VERSION 5.8 ;
BUSBITCHARS "[]" ;
DIVIDERCHAR "/" ;
UNITS
    DATABASE MICRONS 1000 ;
END UNITS

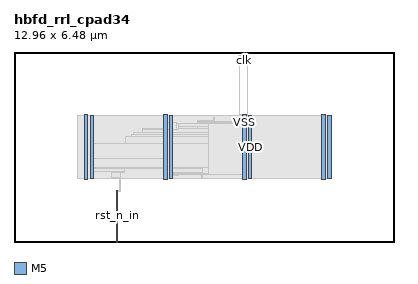
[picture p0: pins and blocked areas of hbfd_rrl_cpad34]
MACRO hbfd_rrl_cpad34
  FOREIGN hbfd_rrl_cpad34 0 0 ;
  CLASS BLOCK ;
  SIZE 12.96 BY 6.48 ;
  PIN clk
    DIRECTION INPUT ;
    USE SIGNAL ;
    PORT
      LAYER M5 ;
        RECT  7.824 6.396 7.848 6.48 ;
    END
  END clk
  PIN rst_n
    DIRECTION OUTPUT ;
    USE SIGNAL ;
    PORT
      LAYER M5 ;
        RECT  7.92 6.396 7.944 6.48 ;
    END
  END rst_n
  PIN rst_n_in
    DIRECTION INPUT ;
    USE SIGNAL ;
    PORT
      LAYER M5 ;
        RECT  3.504 0 3.528 0.084 ;
    END
    PORT
      LAYER M5 ;
        RECT  3.504 0.016 3.528 1.763 ;
    END
  END rst_n_in
  PIN VDD
    DIRECTION INOUT ;
    USE POWER ;
    PORT
      LAYER M5 ;
        RECT  10.692 2.151 10.812 4.329 ;
        RECT  7.992 2.151 8.112 4.329 ;
        RECT  5.292 2.151 5.412 4.329 ;
        RECT  2.592 2.151 2.712 4.329 ;
    END
  END VDD
  PIN VSS
    DIRECTION INOUT ;
    USE GROUND ;
    PORT
      LAYER M5 ;
        RECT  10.5 2.137 10.62 4.343 ;
        RECT  7.8 2.137 7.92 4.343 ;
        RECT  5.1 2.137 5.22 4.343 ;
        RECT  2.4 2.137 2.52 4.343 ;
    END
  END VSS
  # OT_OBS_CLOSED layer=M5 d_um=1.536 added=0
  OBS
    LAYER RVTN ;
     RECT  2.16 2.16 10.8 2.295 ;
     RECT  2.16 2.565 10.8 2.835 ;
     RECT  2.16 3.105 10.8 3.375 ;
     RECT  2.16 3.645 10.8 3.915 ;
     RECT  2.16 4.185 10.8 4.32 ;
    LAYER RVTP ;
     RECT  2.16 2.295 10.8 2.565 ;
     RECT  2.16 2.835 10.8 3.105 ;
     RECT  2.16 3.375 10.8 3.645 ;
     RECT  2.16 3.915 10.8 4.185 ;
    LAYER M1 ;
     RECT  2.16 2.151 10.8 4.329 ;
    LAYER M2 ;
     RECT  2.16 2.151 10.8 4.329 ;
     RECT  10.8 2.421 10.812 4.059 ;
    LAYER M3 ;
     RECT  3.6 1.723 3.618 2.191 ;
     RECT  5.115 2.143 5.205 2.263 ;
     RECT  7.815 2.143 7.905 2.299 ;
     RECT  3.312 2.191 3.618 2.371 ;
     RECT  5.115 2.263 5.598 2.371 ;
     RECT  6.408 2.191 6.426 2.371 ;
     RECT  2.415 2.143 2.505 2.413 ;
     RECT  3.312 2.371 3.762 2.413 ;
     RECT  7.272 2.299 7.905 2.413 ;
     RECT  10.515 2.143 10.605 2.413 ;
     RECT  2.415 2.413 3.762 2.497 ;
     RECT  5.115 2.371 6.426 2.497 ;
     RECT  2.415 2.497 6.426 2.533 ;
     RECT  7.272 2.413 8.097 2.533 ;
     RECT  2.415 2.533 8.097 3.371 ;
     RECT  3.816 3.371 8.097 3.605 ;
     RECT  3.996 3.605 8.097 3.677 ;
     RECT  4.068 3.677 8.097 3.749 ;
     RECT  4.392 3.749 8.097 3.869 ;
     RECT  4.392 3.869 5.454 3.875 ;
     RECT  5.115 3.875 5.454 3.965 ;
     RECT  2.415 3.371 2.697 4.067 ;
     RECT  5.115 3.965 5.397 4.067 ;
     RECT  6.264 3.869 8.097 4.067 ;
     RECT  10.515 2.413 10.797 4.067 ;
     RECT  6.264 4.067 7.974 4.109 ;
     RECT  6.264 4.109 6.822 4.145 ;
     RECT  6.804 4.145 6.822 4.253 ;
     RECT  2.415 4.067 2.505 4.337 ;
     RECT  5.115 4.067 5.205 4.337 ;
     RECT  7.815 4.109 7.974 4.337 ;
     RECT  10.515 4.067 10.605 4.337 ;
     RECT  7.956 4.337 7.974 6.365 ;
    LAYER M4 ;
     RECT  2.408 2.148 2.512 4.332 ;
     RECT  2.512 2.418 2.704 4.062 ;
     RECT  3.493 1.728 3.629 1.752 ;
     RECT  2.704 2.832 5.108 2.856 ;
     RECT  4.381 3.84 5.108 3.864 ;
     RECT  5.108 2.148 5.212 4.332 ;
     RECT  5.212 2.304 5.404 4.062 ;
     RECT  5.404 3.84 5.616 4.056 ;
     RECT  5.404 2.304 6.649 2.328 ;
     RECT  5.616 3.936 6.649 4.056 ;
     RECT  6.649 2.304 7.808 4.056 ;
     RECT  7.808 2.148 7.912 4.332 ;
     RECT  7.669 6.336 7.996 6.36 ;
     RECT  7.912 2.418 8.104 4.062 ;
     RECT  10.508 2.148 10.612 4.332 ;
     RECT  10.612 2.418 10.804 4.062 ;
    LAYER M5 ;
     RECT  2.4 2.137 2.52 2.151 ;
     RECT  5.1 2.137 5.22 2.151 ;
     RECT  7.8 2.137 7.92 2.151 ;
     RECT  10.5 2.137 10.62 2.151 ;
     RECT  5.1 2.151 5.412 3.829 ;
     RECT  7.8 2.151 8.112 3.925 ;
     RECT  5.1 3.829 5.544 4.067 ;
     RECT  2.4 2.151 2.712 4.329 ;
     RECT  5.1 4.067 5.412 4.329 ;
     RECT  7.68 3.925 8.112 4.329 ;
     RECT  10.5 2.151 10.812 4.329 ;
     RECT  2.4 4.329 2.52 4.343 ;
     RECT  5.1 4.329 5.22 4.343 ;
     RECT  7.68 4.329 7.92 4.343 ;
     RECT  10.5 4.329 10.62 4.343 ;
     RECT  7.68 4.343 7.704 6.325 ;
     RECT  7.68 6.325 7.944 6.371 ;
     RECT  7.824 6.371 7.944 6.396 ;
     RECT  7.848 6.396 7.92 6.416 ;
  END
END hbfd_rrl_cpad34
END LIBRARY
